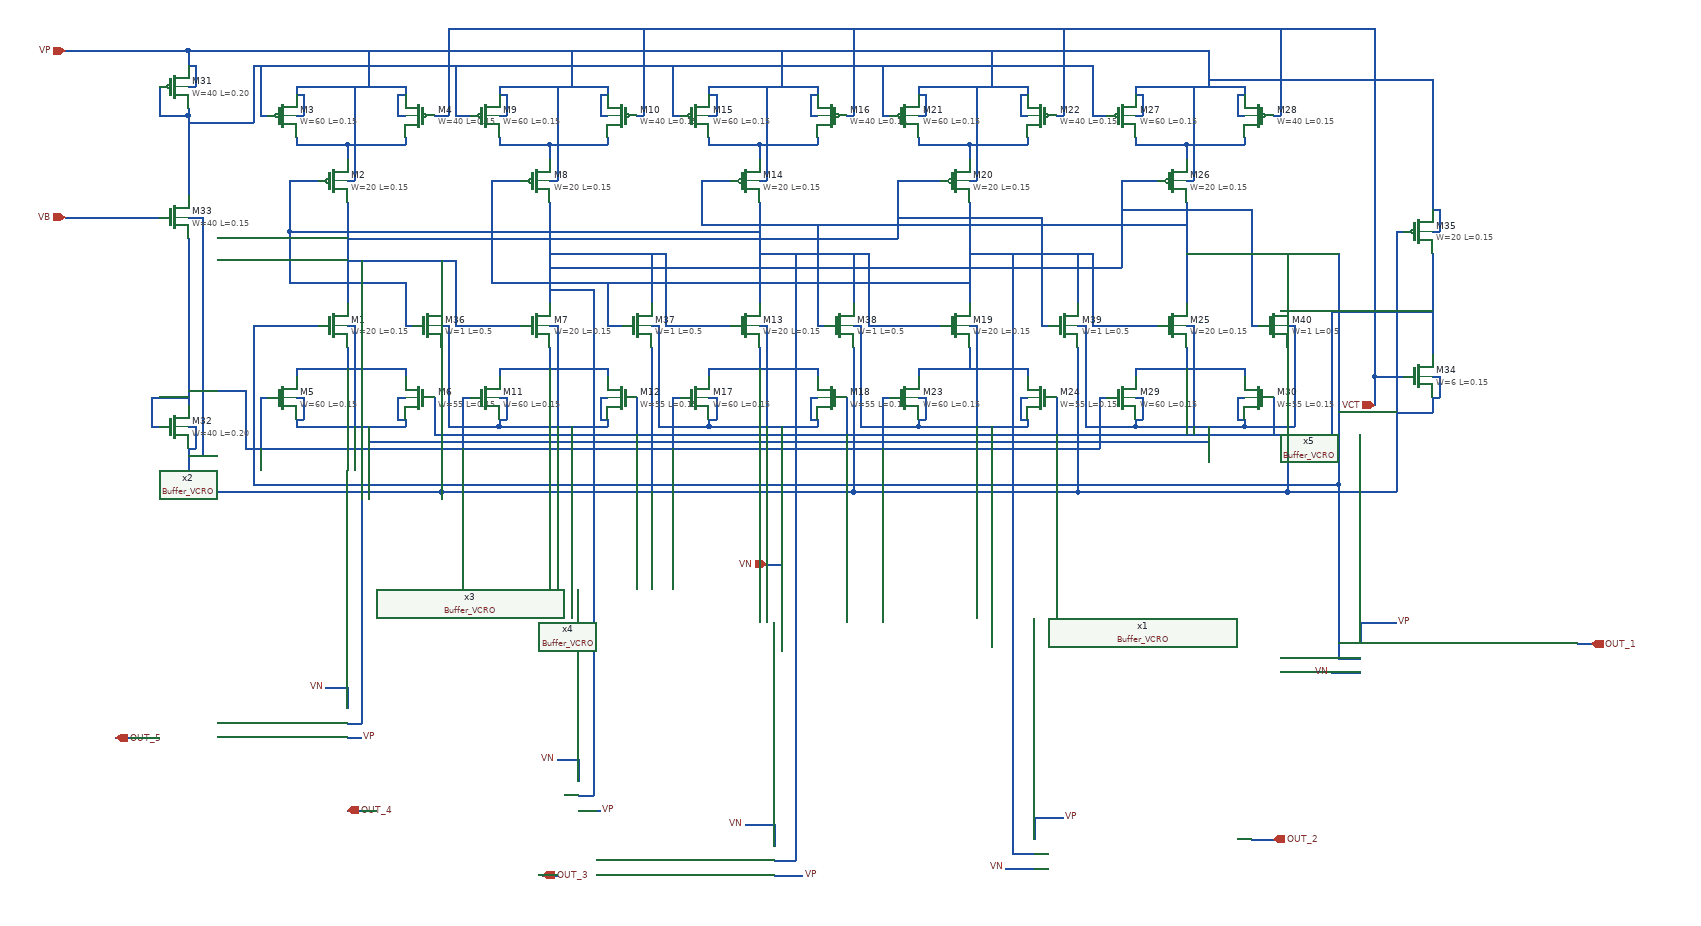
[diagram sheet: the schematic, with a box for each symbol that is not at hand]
v {xschem version=3.0.0 file_version=1.2 }
G {}
K {}
V {}
S {}
E {}
N -180 -140 -180 0 { lab=#net1}
N -180 -170 -170 -170 { lab=VP}
N -170 -200 -170 -170 { lab=VP}
N -180 30 -170 30 { lab=VN}
N -170 30 -170 60 { lab=VN}
N -180 -220 -180 -200 { lab=#net2}
N -250 -230 -250 -220 { lab=#net2}
N -250 -220 -180 -220 { lab=#net2}
N -100 -230 -100 -220 { lab=#net2}
N -180 -220 -100 -220 { lab=#net2}
N -250 -260 -240 -260 { lab=VP}
N -240 -290 -240 -260 { lab=VP}
N -250 -290 -240 -290 { lab=VP}
N -110 -260 -100 -260 { lab=VP}
N -110 -290 -110 -260 { lab=VP}
N -110 -290 -100 -290 { lab=VP}
N -250 -300 -250 -290 { lab=VP}
N -250 -300 -100 -300 { lab=VP}
N -100 -300 -100 -290 { lab=VP}
N -250 90 -250 100 { lab=#net3}
N -250 90 -100 90 { lab=#net3}
N -100 90 -100 100 { lab=#net3}
N -250 130 -240 130 { lab=VN}
N -240 130 -240 160 { lab=VN}
N -250 160 -240 160 { lab=VN}
N -110 130 -100 130 { lab=VN}
N -110 130 -110 160 { lab=VN}
N -110 160 -100 160 { lab=VN}
N -250 160 -250 170 { lab=VN}
N -250 170 -100 170 { lab=VN}
N -100 160 -100 170 { lab=VN}
N -180 60 -180 90 { lab=#net3}
N 100 -140 100 0 { lab=#net4}
N 100 -170 110 -170 { lab=VP}
N 110 -200 110 -170 { lab=VP}
N 100 30 110 30 { lab=VN}
N 110 30 110 60 { lab=VN}
N 100 -220 100 -200 { lab=#net5}
N 30 -230 30 -220 { lab=#net5}
N 30 -220 100 -220 { lab=#net5}
N 180 -230 180 -220 { lab=#net5}
N 100 -220 180 -220 { lab=#net5}
N 30 -260 40 -260 { lab=VP}
N 40 -290 40 -260 { lab=VP}
N 30 -290 40 -290 { lab=VP}
N 170 -260 180 -260 { lab=VP}
N 170 -290 170 -260 { lab=VP}
N 170 -290 180 -290 { lab=VP}
N 30 -300 30 -290 { lab=VP}
N 30 -300 180 -300 { lab=VP}
N 180 -300 180 -290 { lab=VP}
N 30 90 30 100 { lab=#net6}
N 30 90 180 90 { lab=#net6}
N 180 90 180 100 { lab=#net6}
N 30 130 40 130 { lab=VN}
N 40 130 40 160 { lab=VN}
N 30 160 40 160 { lab=VN}
N 170 130 180 130 { lab=VN}
N 170 130 170 160 { lab=VN}
N 170 160 180 160 { lab=VN}
N 30 160 30 170 { lab=VN}
N 30 170 180 170 { lab=VN}
N 180 160 180 170 { lab=VN}
N 100 60 100 90 { lab=#net6}
N 390 -140 390 0 { lab=#net7}
N 390 -170 400 -170 { lab=VP}
N 400 -200 400 -170 { lab=VP}
N 390 30 400 30 { lab=VN}
N 400 30 400 60 { lab=VN}
N 390 -220 390 -200 { lab=#net8}
N 320 -230 320 -220 { lab=#net8}
N 320 -220 390 -220 { lab=#net8}
N 470 -230 470 -220 { lab=#net8}
N 390 -220 470 -220 { lab=#net8}
N 320 -260 330 -260 { lab=VP}
N 330 -290 330 -260 { lab=VP}
N 320 -290 330 -290 { lab=VP}
N 460 -260 470 -260 { lab=VP}
N 460 -290 460 -260 { lab=VP}
N 460 -290 470 -290 { lab=VP}
N 320 -300 320 -290 { lab=VP}
N 320 -300 470 -300 { lab=VP}
N 470 -300 470 -290 { lab=VP}
N 320 90 320 100 { lab=#net9}
N 320 90 470 90 { lab=#net9}
N 470 90 470 100 { lab=#net9}
N 320 130 330 130 { lab=VN}
N 330 130 330 160 { lab=VN}
N 320 160 330 160 { lab=VN}
N 460 130 470 130 { lab=VN}
N 460 130 460 160 { lab=VN}
N 460 160 470 160 { lab=VN}
N 320 160 320 170 { lab=VN}
N 320 170 470 170 { lab=VN}
N 470 160 470 170 { lab=VN}
N 390 60 390 90 { lab=#net9}
N 680 -140 680 0 { lab=#net10}
N 680 -170 690 -170 { lab=VP}
N 690 -200 690 -170 { lab=VP}
N 680 30 690 30 { lab=VN}
N 690 30 690 60 { lab=VN}
N 680 -220 680 -200 { lab=#net11}
N 610 -230 610 -220 { lab=#net11}
N 610 -220 680 -220 { lab=#net11}
N 760 -230 760 -220 { lab=#net11}
N 680 -220 760 -220 { lab=#net11}
N 610 -260 620 -260 { lab=VP}
N 620 -290 620 -260 { lab=VP}
N 610 -290 620 -290 { lab=VP}
N 750 -260 760 -260 { lab=VP}
N 750 -290 750 -260 { lab=VP}
N 750 -290 760 -290 { lab=VP}
N 610 -300 610 -290 { lab=VP}
N 610 -300 760 -300 { lab=VP}
N 760 -300 760 -290 { lab=VP}
N 610 90 610 100 { lab=#net12}
N 610 90 760 90 { lab=#net12}
N 760 90 760 100 { lab=#net12}
N 610 130 620 130 { lab=VN}
N 620 130 620 160 { lab=VN}
N 610 160 620 160 { lab=VN}
N 750 130 760 130 { lab=VN}
N 750 130 750 160 { lab=VN}
N 750 160 760 160 { lab=VN}
N 610 160 610 170 { lab=VN}
N 610 170 760 170 { lab=VN}
N 760 160 760 170 { lab=VN}
N 680 60 680 90 { lab=#net12}
N 980 -140 980 0 { lab=#net13}
N 980 -170 990 -170 { lab=VP}
N 990 -200 990 -170 { lab=VP}
N 980 30 990 30 { lab=VN}
N 990 30 990 60 { lab=VN}
N 980 -220 980 -200 { lab=#net14}
N 910 -230 910 -220 { lab=#net14}
N 910 -220 980 -220 { lab=#net14}
N 1060 -230 1060 -220 { lab=#net14}
N 980 -220 1060 -220 { lab=#net14}
N 910 -260 920 -260 { lab=VP}
N 920 -290 920 -260 { lab=VP}
N 910 -290 920 -290 { lab=VP}
N 1050 -260 1060 -260 { lab=VP}
N 1050 -290 1050 -260 { lab=VP}
N 1050 -290 1060 -290 { lab=VP}
N 910 -300 910 -290 { lab=VP}
N 910 -300 1060 -300 { lab=VP}
N 1060 -300 1060 -290 { lab=VP}
N 910 90 910 100 { lab=#net15}
N 910 90 1060 90 { lab=#net15}
N 1060 90 1060 100 { lab=#net15}
N 910 130 920 130 { lab=VN}
N 920 130 920 160 { lab=VN}
N 910 160 920 160 { lab=VN}
N 1050 130 1060 130 { lab=VN}
N 1050 130 1050 160 { lab=VN}
N 1050 160 1060 160 { lab=VN}
N 910 160 910 170 { lab=VN}
N 910 170 1060 170 { lab=VN}
N 1060 160 1060 170 { lab=VN}
N 980 60 980 90 { lab=#net15}
N -170 -300 -170 -200 { lab=VP}
N 110 -300 110 -200 { lab=VP}
N 400 -300 400 -200 { lab=VP}
N 690 -300 690 -200 { lab=VP}
N 990 -300 990 -200 { lab=VP}
N -170 60 -170 170 { lab=VN}
N 110 60 110 170 { lab=VN}
N 400 60 400 170 { lab=VN}
N 690 60 690 170 { lab=VN}
N 990 60 990 170 { lab=VN}
N -30 30 60 30 { lab=#net1}
N -30 -60 -30 30 { lab=#net1}
N -180 -60 -30 -60 { lab=#net1}
N 260 30 350 30 { lab=#net4}
N 260 -70 260 30 { lab=#net4}
N 100 -70 260 -70 { lab=#net4}
N 540 30 640 30 { lab=#net7}
N 540 -70 540 30 { lab=#net7}
N 390 -70 540 -70 { lab=#net7}
N 680 -70 840 -70 { lab=#net10}
N 850 -70 850 30 { lab=#net10}
N -310 30 -310 250 { lab=#net13}
N 1190 -70 1190 250 { lab=#net13}
N -400 -350 1010 -350 { lab=VP}
N 1010 -340 1010 -300 { lab=VP}
N -150 -340 -150 -300 { lab=VP}
N 130 -340 130 -300 { lab=VP}
N 420 -340 420 -300 { lab=VP}
N 710 -340 710 -300 { lab=VP}
N -150 170 -150 190 { lab=VN}
N -150 190 1010 190 { lab=VN}
N 1010 170 1010 190 { lab=VN}
N 130 170 130 190 { lab=VN}
N 420 170 420 190 { lab=VN}
N 710 170 710 190 { lab=VN}
N 420 190 420 210 { lab=VN}
N -570 -350 -400 -350 { lab=VP}
N 580 -170 640 -170 { lab=#net1}
N 580 -170 580 -90 { lab=#net1}
N -180 -90 580 -90 { lab=#net1}
N 890 -170 940 -170 { lab=#net4}
N 890 -170 890 -50 { lab=#net4}
N 100 -50 890 -50 { lab=#net4}
N -260 -170 -220 -170 { lab=#net7}
N -260 -170 -260 -100 { lab=#net7}
N -260 -100 390 -100 { lab=#net7}
N 20 -170 60 -170 { lab=#net10}
N 20 -170 20 -30 { lab=#net10}
N 20 -30 680 -30 { lab=#net10}
N 310 -170 350 -170 { lab=#net13}
N 310 -170 310 -110 { lab=#net13}
N 310 -110 980 -110 { lab=#net13}
N -310 30 -220 30 { lab=#net13}
N -440 -300 -440 -260 { lab=#net16}
N -440 -260 -400 -260 { lab=#net16}
N -400 -270 -400 -260 { lab=#net16}
N -400 -300 -390 -300 { lab=VP}
N -390 -330 -390 -300 { lab=VP}
N -400 -330 -390 -330 { lab=VP}
N -150 -350 -150 -340 { lab=VP}
N 130 -350 130 -340 { lab=VP}
N 420 -350 420 -340 { lab=VP}
N 710 -350 710 -340 { lab=VP}
N 1010 -350 1010 -340 { lab=VP}
N -400 -350 -400 -330 { lab=VP}
N -400 -90 -400 140 { lab=#net17}
N -400 -260 -400 -150 { lab=#net16}
N -450 170 -440 170 { lab=#net17}
N -450 130 -450 170 { lab=#net17}
N -450 130 -400 130 { lab=#net17}
N -400 120 -320 120 { lab=#net17}
N -320 120 -320 200 { lab=#net17}
N -320 200 860 200 { lab=#net17}
N 860 130 860 200 { lab=#net17}
N 860 130 870 130 { lab=#net17}
N 560 130 570 130 { lab=#net17}
N 560 130 560 200 { lab=#net17}
N 270 130 280 130 { lab=#net17}
N 270 130 270 200 { lab=#net17}
N -20 130 -10 130 { lab=#net17}
N -20 130 -20 200 { lab=#net17}
N -300 130 -290 130 { lab=#net17}
N -300 130 -300 200 { lab=#net17}
N -400 170 -390 170 { lab=VN}
N -390 170 -390 200 { lab=VN}
N -400 200 -390 200 { lab=VN}
N -400 200 -400 230 { lab=VN}
N -400 -250 -310 -250 { lab=#net16}
N -310 -330 -310 -250 { lab=#net16}
N -310 -330 850 -330 { lab=#net16}
N 850 -330 850 -260 { lab=#net16}
N 850 -260 870 -260 { lab=#net16}
N 560 -260 570 -260 { lab=#net16}
N 560 -330 560 -260 { lab=#net16}
N 1240 100 1240 140 { lab=VCT}
N 1240 100 1280 100 { lab=VCT}
N 1320 100 1330 100 { lab=VN}
N 1330 100 1330 130 { lab=VN}
N 1320 130 1330 130 { lab=VN}
N 1320 130 1320 150 { lab=VN}
N 1320 -100 1330 -100 { lab=VP}
N 1330 -130 1330 -100 { lab=VP}
N 1320 -130 1330 -130 { lab=VP}
N 1320 -310 1320 -130 { lab=VP}
N 1010 -310 1320 -310 { lab=VP}
N 1320 -70 1320 70 { lab=#net18}
N 1240 -380 1240 100 { lab=VCT}
N -40 -380 1240 -380 { lab=VCT}
N -40 -380 -40 -260 { lab=VCT}
N -60 -260 -40 -260 { lab=VCT}
N -300 -260 -290 -260 { lab=#net16}
N -300 -330 -300 -260 { lab=#net16}
N -30 -260 -10 -260 { lab=#net16}
N -30 -330 -30 -260 { lab=#net16}
N 270 -260 280 -260 { lab=#net16}
N 270 -330 270 -260 { lab=#net16}
N 220 -260 230 -260 { lab=VCT}
N 230 -380 230 -260 { lab=VCT}
N 510 -260 520 -260 { lab=VCT}
N 520 -380 520 -260 { lab=VCT}
N 800 -260 810 -260 { lab=VCT}
N 810 -380 810 -260 { lab=VCT}
N 1270 -100 1280 -100 { lab=VN}
N 1270 -100 1270 -60 { lab=VN}
N 1220 10 1320 10 { lab=#net18}
N 1180 10 1220 10 { lab=#net18}
N 1180 10 1180 180 { lab=#net18}
N -60 180 1180 180 { lab=#net18}
N -60 130 -60 180 { lab=#net18}
N 220 130 220 180 { lab=#net18}
N 510 130 510 180 { lab=#net18}
N 800 130 800 180 { lab=#net18}
N 1100 130 1100 180 { lab=#net18}
N 1100 -260 1110 -260 { lab=VCT}
N 1110 -380 1110 -260 { lab=VCT}
N 980 -70 1130 -70 { lab=#net13}
N -310 250 1130 250 { lab=#net13}
N 1270 -60 1270 -40 { lab=VN}
N -400 -120 -380 -120 { lab=VN}
N -380 -120 -380 210 { lab=VN}
N -400 210 -380 210 { lab=VN}
N -480 -120 -440 -120 { lab=VB}
N -50 60 -50 260 { lab=VN}
N 240 60 240 260 { lab=VN}
N 520 60 520 260 { lab=VN}
N 830 60 830 260 { lab=VN}
N 1120 60 1120 260 { lab=VN}
N 420 210 420 340 { lab=VN}
N -50 -60 -50 0 { lab=#net1}
N 240 -70 240 0 { lab=#net4}
N 520 -70 520 0 { lab=#net7}
N 830 -70 830 0 { lab=#net10}
N 1120 -70 1120 0 { lab=#net13}
N -100 30 -90 30 { lab=#net7}
N -100 -30 -100 30 { lab=#net7}
N -260 -30 -100 -30 { lab=#net7}
N -260 -100 -260 -30 { lab=#net7}
N 180 30 200 30 { lab=#net10}
N 180 -30 180 30 { lab=#net10}
N 470 30 480 30 { lab=#net13}
N 470 -110 470 30 { lab=#net13}
N 780 30 790 30 { lab=#net1}
N 780 -120 780 30 { lab=#net1}
N 580 -120 780 -120 { lab=#net1}
N 1070 30 1080 30 { lab=#net4}
N 1070 -130 1070 30 { lab=#net4}
N 890 -130 1070 -130 { lab=#net4}
N -50 30 -40 30 { lab=VN}
N -40 30 -40 170 { lab=VN}
N -40 170 30 170 { lab=VN}
N 240 30 250 30 { lab=VN}
N 250 30 250 170 { lab=VN}
N 250 170 320 170 { lab=VN}
N 520 30 530 30 { lab=VN}
N 530 30 530 170 { lab=VN}
N 530 170 610 170 { lab=VN}
N 840 170 910 170 { lab=VN}
N 840 -70 850 -70 { lab=#net10}
N 850 30 940 30 { lab=#net10}
N 830 30 840 30 { lab=VN}
N 840 30 840 170 { lab=VN}
N 1130 250 1190 250 { lab=#net13}
N 1130 -70 1190 -70 { lab=#net13}
N 1120 30 1130 30 { lab=VN}
N 1130 30 1130 170 { lab=VN}
N 1060 170 1130 170 { lab=VN}
N -50 260 420 260 { lab=VN}
N 420 260 520 260 { lab=VN}
N 520 260 830 260 { lab=VN}
N 830 260 1120 260 { lab=VN}
N -400 230 -400 250 { lab=VN}
N -400 250 -400 260 { lab=VN}
N -400 260 -50 260 { lab=VN}
N 1270 -40 1270 260 { lab=VN}
N 1120 260 1270 260 { lab=VN}
N 1270 150 1320 150 { lab=VN}
N 420 340 420 360 { lab=VN}
N 400 360 420 360 { lab=VN}
N -570 -120 -480 -120 { lab=VB}
N 1070 740 1100 740 { lab=OUT_2}
N 440 -70 440 330 { lab=#net7}
N -160 -60 -160 550 { lab=#net1}
N 160 -20 160 400 { lab=#net4}
N 100 -20 150 -20 { lab=#net4}
N 750 760 770 760 { lab=#net10}
N -160 550 -160 580 { lab=#net1}
N -180 580 -160 580 { lab=#net1}
N -500 600 -480 600 { lab=OUT_5}
N 160 400 160 450 { lab=#net4}
N 150 -20 160 -20 { lab=#net4}
N 160 450 160 680 { lab=#net4}
N 140 680 160 680 { lab=#net4}
N -180 700 -160 700 { lab=OUT_4}
N 440 330 440 680 { lab=#net7}
N 440 680 440 770 { lab=#net7}
N 410 770 440 770 { lab=#net7}
N 90 790 110 790 { lab=OUT_3}
N -180 600 -160 600 { lab=#net19}
N -180 530 -180 560 { lab=VN}
N -210 530 -180 530 { lab=VN}
N 140 630 140 660 { lab=VN}
N 110 630 140 630 { lab=VN}
N 140 700 170 700 { lab=VP}
N 410 730 410 750 { lab=VN}
N 410 720 410 730 { lab=VN}
N 370 720 410 720 { lab=VN}
N 410 790 450 790 { lab=VP}
N 740 -70 740 760 { lab=#net10}
N 740 760 750 760 { lab=#net10}
N 770 710 770 740 { lab=VP}
N 770 710 810 710 { lab=VP}
N 730 780 770 780 { lab=VN}
N 1190 250 1190 490 { lab=#net13}
N 1190 490 1220 490 { lab=#net13}
N 1520 470 1540 470 { lab=OUT_1}
N 1220 440 1220 470 { lab=VP}
N 1220 440 1270 440 { lab=VP}
N 1180 510 1220 510 { lab=VN}
C {xschem_sky130/sky130_fd_pr/nfet_01v8.sym} -200 30 0 0 {name=M1
L=0.15
W=20
nf=4 
mult=1
ad="'int((nf+1)/2) * W/nf * 0.29'" 
pd="'2*int((nf+1)/2) * (W/nf + 0.29)'"
as="'int((nf+2)/2) * W/nf * 0.29'" 
ps="'2*int((nf+2)/2) * (W/nf + 0.29)'"
nrd="'0.29 / W'" nrs="'0.29 / W'"
sa=0 sb=0 sd=0
model=nfet_01v8
spiceprefix=X
}
C {xschem_sky130/sky130_fd_pr/pfet_01v8.sym} -200 -170 0 0 {name=M2
L=0.15
W=20
nf=4
mult=1
ad="'int((nf+1)/2) * W/nf * 0.29'" 
pd="'2*int((nf+1)/2) * (W/nf + 0.29)'"
as="'int((nf+2)/2) * W/nf * 0.29'" 
ps="'2*int((nf+2)/2) * (W/nf + 0.29)'"
nrd="'0.29 / W'" nrs="'0.29 / W'"
sa=0 sb=0 sd=0
model=pfet_01v8
spiceprefix=X
}
C {xschem_sky130/sky130_fd_pr/pfet_01v8.sym} -270 -260 0 0 {name=M3
L=0.15
W=60
nf=12
mult=1
ad="'int((nf+1)/2) * W/nf * 0.29'" 
pd="'2*int((nf+1)/2) * (W/nf + 0.29)'"
as="'int((nf+2)/2) * W/nf * 0.29'" 
ps="'2*int((nf+2)/2) * (W/nf + 0.29)'"
nrd="'0.29 / W'" nrs="'0.29 / W'"
sa=0 sb=0 sd=0
model=pfet_01v8
spiceprefix=X
}
C {xschem_sky130/sky130_fd_pr/pfet_01v8.sym} -80 -260 0 1 {name=M4
L=0.15
W=40
nf=8
mult=1
ad="'int((nf+1)/2) * W/nf * 0.29'" 
pd="'2*int((nf+1)/2) * (W/nf + 0.29)'"
as="'int((nf+2)/2) * W/nf * 0.29'" 
ps="'2*int((nf+2)/2) * (W/nf + 0.29)'"
nrd="'0.29 / W'" nrs="'0.29 / W'"
sa=0 sb=0 sd=0
model=pfet_01v8
spiceprefix=X
}
C {xschem_sky130/sky130_fd_pr/nfet_01v8.sym} -270 130 0 0 {name=M5
L=0.15
W=60
nf=12 
mult=1
ad="'int((nf+1)/2) * W/nf * 0.29'" 
pd="'2*int((nf+1)/2) * (W/nf + 0.29)'"
as="'int((nf+2)/2) * W/nf * 0.29'" 
ps="'2*int((nf+2)/2) * (W/nf + 0.29)'"
nrd="'0.29 / W'" nrs="'0.29 / W'"
sa=0 sb=0 sd=0
model=nfet_01v8
spiceprefix=X
}
C {xschem_sky130/sky130_fd_pr/nfet_01v8.sym} -80 130 0 1 {name=M6
L=0.15
W=55
nf=11 
mult=1
ad="'int((nf+1)/2) * W/nf * 0.29'" 
pd="'2*int((nf+1)/2) * (W/nf + 0.29)'"
as="'int((nf+2)/2) * W/nf * 0.29'" 
ps="'2*int((nf+2)/2) * (W/nf + 0.29)'"
nrd="'0.29 / W'" nrs="'0.29 / W'"
sa=0 sb=0 sd=0
model=nfet_01v8
spiceprefix=X
}
C {xschem_sky130/sky130_fd_pr/nfet_01v8.sym} 80 30 0 0 {name=M7
L=0.15
W=20
nf=4 
mult=1
ad="'int((nf+1)/2) * W/nf * 0.29'" 
pd="'2*int((nf+1)/2) * (W/nf + 0.29)'"
as="'int((nf+2)/2) * W/nf * 0.29'" 
ps="'2*int((nf+2)/2) * (W/nf + 0.29)'"
nrd="'0.29 / W'" nrs="'0.29 / W'"
sa=0 sb=0 sd=0
model=nfet_01v8
spiceprefix=X
}
C {xschem_sky130/sky130_fd_pr/pfet_01v8.sym} 80 -170 0 0 {name=M8
L=0.15
W=20
nf=4
mult=1
ad="'int((nf+1)/2) * W/nf * 0.29'" 
pd="'2*int((nf+1)/2) * (W/nf + 0.29)'"
as="'int((nf+2)/2) * W/nf * 0.29'" 
ps="'2*int((nf+2)/2) * (W/nf + 0.29)'"
nrd="'0.29 / W'" nrs="'0.29 / W'"
sa=0 sb=0 sd=0
model=pfet_01v8
spiceprefix=X
}
C {xschem_sky130/sky130_fd_pr/pfet_01v8.sym} 10 -260 0 0 {name=M9
L=0.15
W=60
nf=12
mult=1
ad="'int((nf+1)/2) * W/nf * 0.29'" 
pd="'2*int((nf+1)/2) * (W/nf + 0.29)'"
as="'int((nf+2)/2) * W/nf * 0.29'" 
ps="'2*int((nf+2)/2) * (W/nf + 0.29)'"
nrd="'0.29 / W'" nrs="'0.29 / W'"
sa=0 sb=0 sd=0
model=pfet_01v8
spiceprefix=X
}
C {xschem_sky130/sky130_fd_pr/pfet_01v8.sym} 200 -260 0 1 {name=M10
L=0.15
W=40
nf=8
mult=1
ad="'int((nf+1)/2) * W/nf * 0.29'" 
pd="'2*int((nf+1)/2) * (W/nf + 0.29)'"
as="'int((nf+2)/2) * W/nf * 0.29'" 
ps="'2*int((nf+2)/2) * (W/nf + 0.29)'"
nrd="'0.29 / W'" nrs="'0.29 / W'"
sa=0 sb=0 sd=0
model=pfet_01v8
spiceprefix=X
}
C {xschem_sky130/sky130_fd_pr/nfet_01v8.sym} 10 130 0 0 {name=M11
L=0.15
W=60
nf=12 
mult=1
ad="'int((nf+1)/2) * W/nf * 0.29'" 
pd="'2*int((nf+1)/2) * (W/nf + 0.29)'"
as="'int((nf+2)/2) * W/nf * 0.29'" 
ps="'2*int((nf+2)/2) * (W/nf + 0.29)'"
nrd="'0.29 / W'" nrs="'0.29 / W'"
sa=0 sb=0 sd=0
model=nfet_01v8
spiceprefix=X
}
C {xschem_sky130/sky130_fd_pr/nfet_01v8.sym} 200 130 0 1 {name=M12
L=0.15
W=55
nf=11 
mult=1
ad="'int((nf+1)/2) * W/nf * 0.29'" 
pd="'2*int((nf+1)/2) * (W/nf + 0.29)'"
as="'int((nf+2)/2) * W/nf * 0.29'" 
ps="'2*int((nf+2)/2) * (W/nf + 0.29)'"
nrd="'0.29 / W'" nrs="'0.29 / W'"
sa=0 sb=0 sd=0
model=nfet_01v8
spiceprefix=X
}
C {xschem_sky130/sky130_fd_pr/nfet_01v8.sym} 370 30 0 0 {name=M13
L=0.15
W=20
nf=4 
mult=1
ad="'int((nf+1)/2) * W/nf * 0.29'" 
pd="'2*int((nf+1)/2) * (W/nf + 0.29)'"
as="'int((nf+2)/2) * W/nf * 0.29'" 
ps="'2*int((nf+2)/2) * (W/nf + 0.29)'"
nrd="'0.29 / W'" nrs="'0.29 / W'"
sa=0 sb=0 sd=0
model=nfet_01v8
spiceprefix=X
}
C {xschem_sky130/sky130_fd_pr/pfet_01v8.sym} 370 -170 0 0 {name=M14
L=0.15
W=20
nf=4
mult=1
ad="'int((nf+1)/2) * W/nf * 0.29'" 
pd="'2*int((nf+1)/2) * (W/nf + 0.29)'"
as="'int((nf+2)/2) * W/nf * 0.29'" 
ps="'2*int((nf+2)/2) * (W/nf + 0.29)'"
nrd="'0.29 / W'" nrs="'0.29 / W'"
sa=0 sb=0 sd=0
model=pfet_01v8
spiceprefix=X
}
C {xschem_sky130/sky130_fd_pr/pfet_01v8.sym} 300 -260 0 0 {name=M15
L=0.15
W=60
nf=12
mult=1
ad="'int((nf+1)/2) * W/nf * 0.29'" 
pd="'2*int((nf+1)/2) * (W/nf + 0.29)'"
as="'int((nf+2)/2) * W/nf * 0.29'" 
ps="'2*int((nf+2)/2) * (W/nf + 0.29)'"
nrd="'0.29 / W'" nrs="'0.29 / W'"
sa=0 sb=0 sd=0
model=pfet_01v8
spiceprefix=X
}
C {xschem_sky130/sky130_fd_pr/pfet_01v8.sym} 490 -260 0 1 {name=M16
L=0.15
W=40
nf=8
mult=1
ad="'int((nf+1)/2) * W/nf * 0.29'" 
pd="'2*int((nf+1)/2) * (W/nf + 0.29)'"
as="'int((nf+2)/2) * W/nf * 0.29'" 
ps="'2*int((nf+2)/2) * (W/nf + 0.29)'"
nrd="'0.29 / W'" nrs="'0.29 / W'"
sa=0 sb=0 sd=0
model=pfet_01v8
spiceprefix=X
}
C {xschem_sky130/sky130_fd_pr/nfet_01v8.sym} 300 130 0 0 {name=M17
L=0.15
W=60
nf=12 
mult=1
ad="'int((nf+1)/2) * W/nf * 0.29'" 
pd="'2*int((nf+1)/2) * (W/nf + 0.29)'"
as="'int((nf+2)/2) * W/nf * 0.29'" 
ps="'2*int((nf+2)/2) * (W/nf + 0.29)'"
nrd="'0.29 / W'" nrs="'0.29 / W'"
sa=0 sb=0 sd=0
model=nfet_01v8
spiceprefix=X
}
C {xschem_sky130/sky130_fd_pr/nfet_01v8.sym} 490 130 0 1 {name=M18
L=0.15
W=55
nf=11 
mult=1
ad="'int((nf+1)/2) * W/nf * 0.29'" 
pd="'2*int((nf+1)/2) * (W/nf + 0.29)'"
as="'int((nf+2)/2) * W/nf * 0.29'" 
ps="'2*int((nf+2)/2) * (W/nf + 0.29)'"
nrd="'0.29 / W'" nrs="'0.29 / W'"
sa=0 sb=0 sd=0
model=nfet_01v8
spiceprefix=X
}
C {xschem_sky130/sky130_fd_pr/nfet_01v8.sym} 660 30 0 0 {name=M19
L=0.15
W=20
nf=4 
mult=1
ad="'int((nf+1)/2) * W/nf * 0.29'" 
pd="'2*int((nf+1)/2) * (W/nf + 0.29)'"
as="'int((nf+2)/2) * W/nf * 0.29'" 
ps="'2*int((nf+2)/2) * (W/nf + 0.29)'"
nrd="'0.29 / W'" nrs="'0.29 / W'"
sa=0 sb=0 sd=0
model=nfet_01v8
spiceprefix=X
}
C {xschem_sky130/sky130_fd_pr/pfet_01v8.sym} 660 -170 0 0 {name=M20
L=0.15
W=20
nf=4
mult=1
ad="'int((nf+1)/2) * W/nf * 0.29'" 
pd="'2*int((nf+1)/2) * (W/nf + 0.29)'"
as="'int((nf+2)/2) * W/nf * 0.29'" 
ps="'2*int((nf+2)/2) * (W/nf + 0.29)'"
nrd="'0.29 / W'" nrs="'0.29 / W'"
sa=0 sb=0 sd=0
model=pfet_01v8
spiceprefix=X
}
C {xschem_sky130/sky130_fd_pr/pfet_01v8.sym} 590 -260 0 0 {name=M21
L=0.15
W=60
nf=12
mult=1
ad="'int((nf+1)/2) * W/nf * 0.29'" 
pd="'2*int((nf+1)/2) * (W/nf + 0.29)'"
as="'int((nf+2)/2) * W/nf * 0.29'" 
ps="'2*int((nf+2)/2) * (W/nf + 0.29)'"
nrd="'0.29 / W'" nrs="'0.29 / W'"
sa=0 sb=0 sd=0
model=pfet_01v8
spiceprefix=X
}
C {xschem_sky130/sky130_fd_pr/pfet_01v8.sym} 780 -260 0 1 {name=M22
L=0.15
W=40
nf=8
mult=1
ad="'int((nf+1)/2) * W/nf * 0.29'" 
pd="'2*int((nf+1)/2) * (W/nf + 0.29)'"
as="'int((nf+2)/2) * W/nf * 0.29'" 
ps="'2*int((nf+2)/2) * (W/nf + 0.29)'"
nrd="'0.29 / W'" nrs="'0.29 / W'"
sa=0 sb=0 sd=0
model=pfet_01v8
spiceprefix=X
}
C {xschem_sky130/sky130_fd_pr/nfet_01v8.sym} 590 130 0 0 {name=M23
L=0.15
W=60
nf=12 
mult=1
ad="'int((nf+1)/2) * W/nf * 0.29'" 
pd="'2*int((nf+1)/2) * (W/nf + 0.29)'"
as="'int((nf+2)/2) * W/nf * 0.29'" 
ps="'2*int((nf+2)/2) * (W/nf + 0.29)'"
nrd="'0.29 / W'" nrs="'0.29 / W'"
sa=0 sb=0 sd=0
model=nfet_01v8
spiceprefix=X
}
C {xschem_sky130/sky130_fd_pr/nfet_01v8.sym} 780 130 0 1 {name=M24
L=0.15
W=55
nf=11 
mult=1
ad="'int((nf+1)/2) * W/nf * 0.29'" 
pd="'2*int((nf+1)/2) * (W/nf + 0.29)'"
as="'int((nf+2)/2) * W/nf * 0.29'" 
ps="'2*int((nf+2)/2) * (W/nf + 0.29)'"
nrd="'0.29 / W'" nrs="'0.29 / W'"
sa=0 sb=0 sd=0
model=nfet_01v8
spiceprefix=X
}
C {xschem_sky130/sky130_fd_pr/nfet_01v8.sym} 960 30 0 0 {name=M25
L=0.15
W=20
nf=4 
mult=1
ad="'int((nf+1)/2) * W/nf * 0.29'" 
pd="'2*int((nf+1)/2) * (W/nf + 0.29)'"
as="'int((nf+2)/2) * W/nf * 0.29'" 
ps="'2*int((nf+2)/2) * (W/nf + 0.29)'"
nrd="'0.29 / W'" nrs="'0.29 / W'"
sa=0 sb=0 sd=0
model=nfet_01v8
spiceprefix=X
}
C {xschem_sky130/sky130_fd_pr/pfet_01v8.sym} 960 -170 0 0 {name=M26
L=0.15
W=20
nf=4
mult=1
ad="'int((nf+1)/2) * W/nf * 0.29'" 
pd="'2*int((nf+1)/2) * (W/nf + 0.29)'"
as="'int((nf+2)/2) * W/nf * 0.29'" 
ps="'2*int((nf+2)/2) * (W/nf + 0.29)'"
nrd="'0.29 / W'" nrs="'0.29 / W'"
sa=0 sb=0 sd=0
model=pfet_01v8
spiceprefix=X
}
C {xschem_sky130/sky130_fd_pr/pfet_01v8.sym} 890 -260 0 0 {name=M27
L=0.15
W=60
nf=12
mult=1
ad="'int((nf+1)/2) * W/nf * 0.29'" 
pd="'2*int((nf+1)/2) * (W/nf + 0.29)'"
as="'int((nf+2)/2) * W/nf * 0.29'" 
ps="'2*int((nf+2)/2) * (W/nf + 0.29)'"
nrd="'0.29 / W'" nrs="'0.29 / W'"
sa=0 sb=0 sd=0
model=pfet_01v8
spiceprefix=X
}
C {xschem_sky130/sky130_fd_pr/pfet_01v8.sym} 1080 -260 0 1 {name=M28
L=0.15
W=40
nf=8
mult=1
ad="'int((nf+1)/2) * W/nf * 0.29'" 
pd="'2*int((nf+1)/2) * (W/nf + 0.29)'"
as="'int((nf+2)/2) * W/nf * 0.29'" 
ps="'2*int((nf+2)/2) * (W/nf + 0.29)'"
nrd="'0.29 / W'" nrs="'0.29 / W'"
sa=0 sb=0 sd=0
model=pfet_01v8
spiceprefix=X
}
C {xschem_sky130/sky130_fd_pr/nfet_01v8.sym} 890 130 0 0 {name=M29
L=0.15
W=60
nf=12 
mult=1
ad="'int((nf+1)/2) * W/nf * 0.29'" 
pd="'2*int((nf+1)/2) * (W/nf + 0.29)'"
as="'int((nf+2)/2) * W/nf * 0.29'" 
ps="'2*int((nf+2)/2) * (W/nf + 0.29)'"
nrd="'0.29 / W'" nrs="'0.29 / W'"
sa=0 sb=0 sd=0
model=nfet_01v8
spiceprefix=X
}
C {xschem_sky130/sky130_fd_pr/nfet_01v8.sym} 1080 130 0 1 {name=M30
L=0.15
W=55
nf=11 
mult=1
ad="'int((nf+1)/2) * W/nf * 0.29'" 
pd="'2*int((nf+1)/2) * (W/nf + 0.29)'"
as="'int((nf+2)/2) * W/nf * 0.29'" 
ps="'2*int((nf+2)/2) * (W/nf + 0.29)'"
nrd="'0.29 / W'" nrs="'0.29 / W'"
sa=0 sb=0 sd=0
model=nfet_01v8
spiceprefix=X
}
C {xschem_sky130/sky130_fd_pr/pfet_01v8.sym} -420 -300 0 0 {name=M31
L=0.20
W=40
nf=8
mult=1
ad="'int((nf+1)/2) * W/nf * 0.29'" 
pd="'2*int((nf+1)/2) * (W/nf + 0.29)'"
as="'int((nf+2)/2) * W/nf * 0.29'" 
ps="'2*int((nf+2)/2) * (W/nf + 0.29)'"
nrd="'0.29 / W'" nrs="'0.29 / W'"
sa=0 sb=0 sd=0
model=pfet_01v8
spiceprefix=X
}
C {xschem_sky130/sky130_fd_pr/nfet_01v8.sym} -420 170 0 0 {name=M32
L=0.20
W=40
nf=8
mult=1
ad="'int((nf+1)/2) * W/nf * 0.29'" 
pd="'2*int((nf+1)/2) * (W/nf + 0.29)'"
as="'int((nf+2)/2) * W/nf * 0.29'" 
ps="'2*int((nf+2)/2) * (W/nf + 0.29)'"
nrd="'0.29 / W'" nrs="'0.29 / W'"
sa=0 sb=0 sd=0
model=nfet_01v8
spiceprefix=X
}
C {xschem_sky130/sky130_fd_pr/nfet_01v8.sym} 1300 100 0 0 {name=M34
L=0.15
W=6
nf=1 
mult=1
ad="'int((nf+1)/2) * W/nf * 0.29'" 
pd="'2*int((nf+1)/2) * (W/nf + 0.29)'"
as="'int((nf+2)/2) * W/nf * 0.29'" 
ps="'2*int((nf+2)/2) * (W/nf + 0.29)'"
nrd="'0.29 / W'" nrs="'0.29 / W'"
sa=0 sb=0 sd=0
model=nfet_01v8
spiceprefix=X
}
C {xschem_sky130/sky130_fd_pr/pfet_01v8.sym} 1300 -100 0 0 {name=M35
L=0.15
W=20
nf=4
mult=1
ad="'int((nf+1)/2) * W/nf * 0.29'" 
pd="'2*int((nf+1)/2) * (W/nf + 0.29)'"
as="'int((nf+2)/2) * W/nf * 0.29'" 
ps="'2*int((nf+2)/2) * (W/nf + 0.29)'"
nrd="'0.29 / W'" nrs="'0.29 / W'"
sa=0 sb=0 sd=0
model=pfet_01v8
spiceprefix=X
}
C {xschem_sky130/sky130_fd_pr/nfet_01v8.sym} -420 -120 0 0 {name=M33
L=0.15
W=40
nf=8
mult=1
ad="'int((nf+1)/2) * W/nf * 0.29'" 
pd="'2*int((nf+1)/2) * (W/nf + 0.29)'"
as="'int((nf+2)/2) * W/nf * 0.29'" 
ps="'2*int((nf+2)/2) * (W/nf + 0.29)'"
nrd="'0.29 / W'" nrs="'0.29 / W'"
sa=0 sb=0 sd=0
model=nfet_01v8
spiceprefix=X
}
C {xschem_sky130/sky130_fd_pr/nfet_01v8.sym} -70 30 0 0 {name=M36
L=0.5
W=1
nf=1
mult=1
ad="'int((nf+1)/2) * W/nf * 0.29'" 
pd="'2*int((nf+1)/2) * (W/nf + 0.29)'"
as="'int((nf+2)/2) * W/nf * 0.29'" 
ps="'2*int((nf+2)/2) * (W/nf + 0.29)'"
nrd="'0.29 / W'" nrs="'0.29 / W'"
sa=0 sb=0 sd=0
model=nfet_01v8
spiceprefix=X
}
C {xschem_sky130/sky130_fd_pr/nfet_01v8.sym} 220 30 0 0 {name=M37
L=0.5
W=1
nf=1 
mult=1
ad="'int((nf+1)/2) * W/nf * 0.29'" 
pd="'2*int((nf+1)/2) * (W/nf + 0.29)'"
as="'int((nf+2)/2) * W/nf * 0.29'" 
ps="'2*int((nf+2)/2) * (W/nf + 0.29)'"
nrd="'0.29 / W'" nrs="'0.29 / W'"
sa=0 sb=0 sd=0
model=nfet_01v8
spiceprefix=X
}
C {xschem_sky130/sky130_fd_pr/nfet_01v8.sym} 500 30 0 0 {name=M38
L=0.5
W=1
nf=1 
mult=1
ad="'int((nf+1)/2) * W/nf * 0.29'" 
pd="'2*int((nf+1)/2) * (W/nf + 0.29)'"
as="'int((nf+2)/2) * W/nf * 0.29'" 
ps="'2*int((nf+2)/2) * (W/nf + 0.29)'"
nrd="'0.29 / W'" nrs="'0.29 / W'"
sa=0 sb=0 sd=0
model=nfet_01v8
spiceprefix=X
}
C {xschem_sky130/sky130_fd_pr/nfet_01v8.sym} 810 30 0 0 {name=M39
L=0.5
W=1
nf=1 
mult=1
ad="'int((nf+1)/2) * W/nf * 0.29'" 
pd="'2*int((nf+1)/2) * (W/nf + 0.29)'"
as="'int((nf+2)/2) * W/nf * 0.29'" 
ps="'2*int((nf+2)/2) * (W/nf + 0.29)'"
nrd="'0.29 / W'" nrs="'0.29 / W'"
sa=0 sb=0 sd=0
model=nfet_01v8
spiceprefix=X
}
C {xschem_sky130/sky130_fd_pr/nfet_01v8.sym} 1100 30 0 0 {name=M40
L=0.5
W=1
nf=1 
mult=1
ad="'int((nf+1)/2) * W/nf * 0.29'" 
pd="'2*int((nf+1)/2) * (W/nf + 0.29)'"
as="'int((nf+2)/2) * W/nf * 0.29'" 
ps="'2*int((nf+2)/2) * (W/nf + 0.29)'"
nrd="'0.29 / W'" nrs="'0.29 / W'"
sa=0 sb=0 sd=0
model=nfet_01v8
spiceprefix=X
}
C {ipin.sym} -570 -350 0 0 {name=p1 lab=VP}
C {ipin.sym} 1240 140 3 0 {name=p2 lab=VCT}
C {opin.sym} 1540 470 0 0 {name=p3 lab=OUT_1}
C {ipin.sym} 400 360 0 0 {name=p4 lab=VN}
C {ipin.sym} -570 -120 0 0 {name=p5 lab=VB}
C {opin.sym} -180 700 2 0 {name=p6 lab=OUT_4}
C {opin.sym} 90 790 2 0 {name=p7 lab=OUT_3}
C {opin.sym} 1100 740 0 0 {name=p8 lab=OUT_2}
C {opin.sym} -500 600 2 0 {name=p9 lab=OUT_5}
C {Anchit_Tests/Buffer_VCRO.sym} 920 760 0 0 {name=x1}
C {Anchit_Tests/Buffer_VCRO.sym} -330 580 2 0 {name=x2}
C {Anchit_Tests/Buffer_VCRO.sym} -10 680 2 0 {name=x3}
C {Anchit_Tests/Buffer_VCRO.sym} 260 770 2 0 {name=x4}
C {Anchit_Tests/Buffer_VCRO.sym} 1370 490 0 0 {name=x5}
C {lab_pin.sym} 1180 510 0 0 {name=l1 sig_type=std_logic lab=VN}
C {lab_pin.sym} 730 780 0 0 {name=l2 sig_type=std_logic lab=VN}
C {lab_pin.sym} 370 720 0 0 {name=l3 sig_type=std_logic lab=VN}
C {lab_pin.sym} 110 630 0 0 {name=l4 sig_type=std_logic lab=VN}
C {lab_pin.sym} -210 530 0 0 {name=l5 sig_type=std_logic lab=VN}
C {lab_pin.sym} 810 710 2 0 {name=l6 sig_type=std_logic lab=VP}
C {lab_pin.sym} 1270 440 2 0 {name=l7 sig_type=std_logic lab=VP}
C {lab_pin.sym} 450 790 2 0 {name=l8 sig_type=std_logic lab=VP}
C {lab_pin.sym} 170 700 2 0 {name=l9 sig_type=std_logic lab=VP}
C {lab_pin.sym} -160 600 2 0 {name=l10 sig_type=std_logic lab=VP}
